VERSION 5.7 ;
  NOWIREEXTENSIONATPIN ON ;
  DIVIDERCHAR "/" ;
  BUSBITCHARS "[]" ;
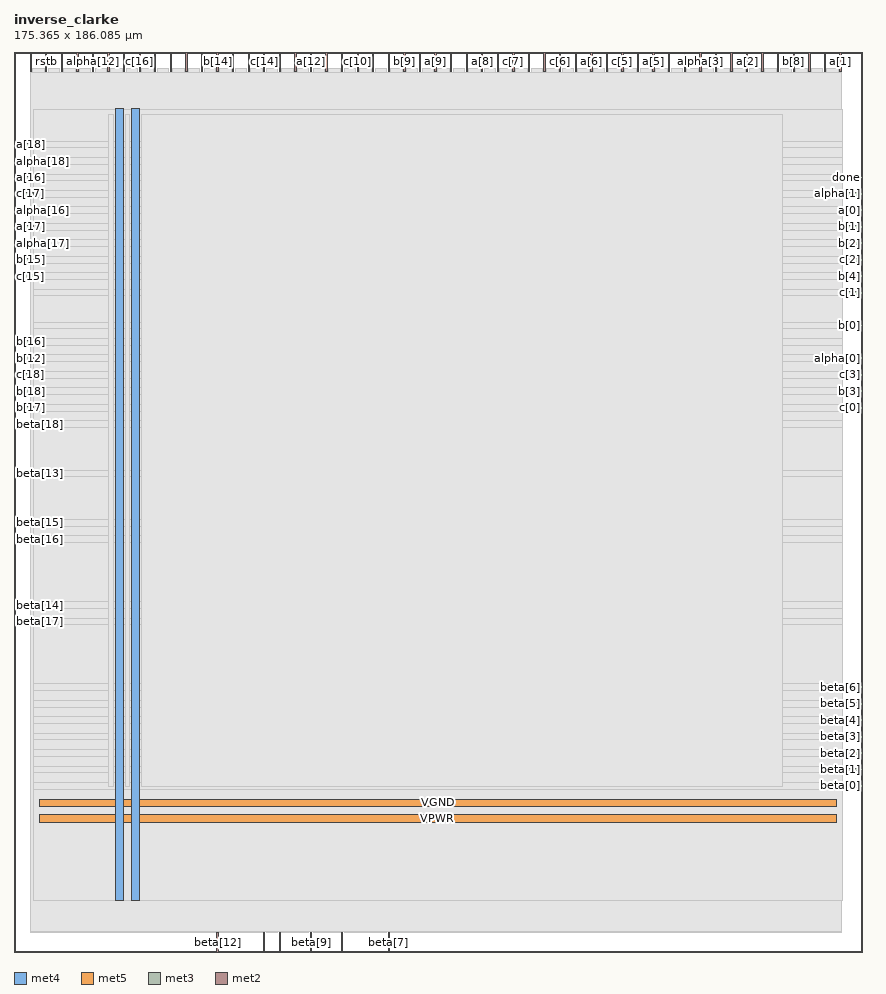
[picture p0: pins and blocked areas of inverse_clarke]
MACRO inverse_clarke
  CLASS BLOCK ;
  FOREIGN inverse_clarke ;
  ORIGIN 0.000 0.000 ;
  SIZE 175.365 BY 186.085 ;
  PIN VGND
    DIRECTION INOUT ;
    USE GROUND ;
    PORT
      LAYER met4 ;
        RECT 24.340 10.640 25.940 174.320 ;
    END
    PORT
      LAYER met5 ;
        RECT 5.280 30.030 169.980 31.630 ;
    END
  END VGND
  PIN VPWR
    DIRECTION INOUT ;
    USE POWER ;
    PORT
      LAYER met4 ;
        RECT 21.040 10.640 22.640 174.320 ;
    END
    PORT
      LAYER met5 ;
        RECT 5.280 26.730 169.980 28.330 ;
    END
  END VPWR
  PIN a[0]
    DIRECTION OUTPUT ;
    USE SIGNAL ;
    ANTENNADIFFAREA 0.795200 ;
    PORT
      LAYER met3 ;
        RECT 171.365 153.040 175.365 153.640 ;
    END
  END a[0]
  PIN a[10]
    DIRECTION OUTPUT ;
    USE SIGNAL ;
    ANTENNADIFFAREA 0.795200 ;
    PORT
      LAYER met2 ;
        RECT 12.970 182.085 13.250 186.085 ;
    END
  END a[10]
  PIN a[11]
    DIRECTION OUTPUT ;
    USE SIGNAL ;
    ANTENNADIFFAREA 0.445500 ;
    PORT
      LAYER met2 ;
        RECT 45.170 182.085 45.450 186.085 ;
    END
  END a[11]
  PIN a[12]
    DIRECTION OUTPUT ;
    USE SIGNAL ;
    ANTENNADIFFAREA 0.795200 ;
    PORT
      LAYER met2 ;
        RECT 61.270 182.085 61.550 186.085 ;
    END
  END a[12]
  PIN a[13]
    DIRECTION OUTPUT ;
    USE SIGNAL ;
    ANTENNADIFFAREA 0.795200 ;
    PORT
      LAYER met2 ;
        RECT 19.410 182.085 19.690 186.085 ;
    END
  END a[13]
  PIN a[14]
    DIRECTION OUTPUT ;
    USE SIGNAL ;
    ANTENNADIFFAREA 0.795200 ;
    PORT
      LAYER met2 ;
        RECT 32.290 182.085 32.570 186.085 ;
    END
  END a[14]
  PIN a[15]
    DIRECTION OUTPUT ;
    USE SIGNAL ;
    ANTENNADIFFAREA 0.795200 ;
    PORT
      LAYER met2 ;
        RECT 29.070 182.085 29.350 186.085 ;
    END
  END a[15]
  PIN a[16]
    DIRECTION OUTPUT ;
    USE SIGNAL ;
    ANTENNADIFFAREA 0.795200 ;
    PORT
      LAYER met3 ;
        RECT 0.000 159.840 4.000 160.440 ;
    END
  END a[16]
  PIN a[17]
    DIRECTION OUTPUT ;
    USE SIGNAL ;
    ANTENNADIFFAREA 0.795200 ;
    PORT
      LAYER met3 ;
        RECT 0.000 149.640 4.000 150.240 ;
    END
  END a[17]
  PIN a[18]
    DIRECTION OUTPUT ;
    USE SIGNAL ;
    ANTENNADIFFAREA 0.795200 ;
    PORT
      LAYER met3 ;
        RECT 0.000 166.640 4.000 167.240 ;
    END
  END a[18]
  PIN a[1]
    DIRECTION OUTPUT ;
    USE SIGNAL ;
    ANTENNADIFFAREA 0.795200 ;
    PORT
      LAYER met2 ;
        RECT 170.750 182.085 171.030 186.085 ;
    END
  END a[1]
  PIN a[2]
    DIRECTION OUTPUT ;
    USE SIGNAL ;
    ANTENNADIFFAREA 0.795200 ;
    PORT
      LAYER met2 ;
        RECT 151.430 182.085 151.710 186.085 ;
    END
  END a[2]
  PIN a[3]
    DIRECTION OUTPUT ;
    USE SIGNAL ;
    ANTENNADIFFAREA 0.795200 ;
    PORT
      LAYER met2 ;
        RECT 148.210 182.085 148.490 186.085 ;
    END
  END a[3]
  PIN a[4]
    DIRECTION OUTPUT ;
    USE SIGNAL ;
    ANTENNADIFFAREA 0.795200 ;
    PORT
      LAYER met2 ;
        RECT 154.650 182.085 154.930 186.085 ;
    END
  END a[4]
  PIN a[5]
    DIRECTION OUTPUT ;
    USE SIGNAL ;
    ANTENNADIFFAREA 0.795200 ;
    PORT
      LAYER met2 ;
        RECT 132.110 182.085 132.390 186.085 ;
    END
  END a[5]
  PIN a[6]
    DIRECTION OUTPUT ;
    USE SIGNAL ;
    ANTENNADIFFAREA 0.795200 ;
    PORT
      LAYER met2 ;
        RECT 119.230 182.085 119.510 186.085 ;
    END
  END a[6]
  PIN a[7]
    DIRECTION OUTPUT ;
    USE SIGNAL ;
    ANTENNADIFFAREA 0.795200 ;
    PORT
      LAYER met2 ;
        RECT 167.530 182.085 167.810 186.085 ;
    END
  END a[7]
  PIN a[8]
    DIRECTION OUTPUT ;
    USE SIGNAL ;
    ANTENNADIFFAREA 0.795200 ;
    PORT
      LAYER met2 ;
        RECT 96.690 182.085 96.970 186.085 ;
    END
  END a[8]
  PIN a[9]
    DIRECTION OUTPUT ;
    USE SIGNAL ;
    ANTENNADIFFAREA 0.795200 ;
    PORT
      LAYER met2 ;
        RECT 87.030 182.085 87.310 186.085 ;
    END
  END a[9]
  PIN alpha[0]
    DIRECTION INPUT ;
    USE SIGNAL ;
    ANTENNAGATEAREA 0.196500 ;
    PORT
      LAYER met3 ;
        RECT 171.365 122.440 175.365 123.040 ;
    END
  END alpha[0]
  PIN alpha[10]
    DIRECTION INPUT ;
    USE SIGNAL ;
    ANTENNAGATEAREA 0.213000 ;
    PORT
      LAYER met2 ;
        RECT 54.830 182.085 55.110 186.085 ;
    END
  END alpha[10]
  PIN alpha[11]
    DIRECTION INPUT ;
    USE SIGNAL ;
    ANTENNAGATEAREA 0.196500 ;
    PORT
      LAYER met2 ;
        RECT 74.150 182.085 74.430 186.085 ;
    END
  END alpha[11]
  PIN alpha[12]
    DIRECTION INPUT ;
    USE SIGNAL ;
    ANTENNAGATEAREA 0.196500 ;
    PORT
      LAYER met2 ;
        RECT 16.190 182.085 16.470 186.085 ;
    END
  END alpha[12]
  PIN alpha[13]
    DIRECTION INPUT ;
    USE SIGNAL ;
    ANTENNAGATEAREA 0.159000 ;
    PORT
      LAYER met2 ;
        RECT 35.510 182.085 35.790 186.085 ;
    END
  END alpha[13]
  PIN alpha[14]
    DIRECTION INPUT ;
    USE SIGNAL ;
    ANTENNAGATEAREA 0.196500 ;
    PORT
      LAYER met2 ;
        RECT 38.730 182.085 39.010 186.085 ;
    END
  END alpha[14]
  PIN alpha[15]
    DIRECTION INPUT ;
    USE SIGNAL ;
    ANTENNAGATEAREA 0.196500 ;
    PORT
      LAYER met2 ;
        RECT 22.630 182.085 22.910 186.085 ;
    END
  END alpha[15]
  PIN alpha[16]
    DIRECTION INPUT ;
    USE SIGNAL ;
    ANTENNAGATEAREA 0.196500 ;
    PORT
      LAYER met3 ;
        RECT 0.000 153.040 4.000 153.640 ;
    END
  END alpha[16]
  PIN alpha[17]
    DIRECTION INPUT ;
    USE SIGNAL ;
    ANTENNAGATEAREA 0.196500 ;
    PORT
      LAYER met3 ;
        RECT 0.000 146.240 4.000 146.840 ;
    END
  END alpha[17]
  PIN alpha[18]
    DIRECTION INPUT ;
    USE SIGNAL ;
    ANTENNAGATEAREA 0.196500 ;
    PORT
      LAYER met3 ;
        RECT 0.000 163.240 4.000 163.840 ;
    END
  END alpha[18]
  PIN alpha[1]
    DIRECTION INPUT ;
    USE SIGNAL ;
    ANTENNAGATEAREA 0.196500 ;
    PORT
      LAYER met3 ;
        RECT 171.365 156.440 175.365 157.040 ;
    END
  END alpha[1]
  PIN alpha[2]
    DIRECTION INPUT ;
    USE SIGNAL ;
    ANTENNAGATEAREA 0.213000 ;
    PORT
      LAYER met2 ;
        RECT 144.990 182.085 145.270 186.085 ;
    END
  END alpha[2]
  PIN alpha[3]
    DIRECTION INPUT ;
    USE SIGNAL ;
    ANTENNAGATEAREA 0.196500 ;
    PORT
      LAYER met2 ;
        RECT 141.770 182.085 142.050 186.085 ;
    END
  END alpha[3]
  PIN alpha[4]
    DIRECTION INPUT ;
    USE SIGNAL ;
    ANTENNAGATEAREA 0.213000 ;
    PORT
      LAYER met2 ;
        RECT 138.550 182.085 138.830 186.085 ;
    END
  END alpha[4]
  PIN alpha[5]
    DIRECTION INPUT ;
    USE SIGNAL ;
    ANTENNAGATEAREA 0.196500 ;
    PORT
      LAYER met2 ;
        RECT 128.890 182.085 129.170 186.085 ;
    END
  END alpha[5]
  PIN alpha[6]
    DIRECTION INPUT ;
    USE SIGNAL ;
    ANTENNAGATEAREA 0.196500 ;
    PORT
      LAYER met2 ;
        RECT 157.870 182.085 158.150 186.085 ;
    END
  END alpha[6]
  PIN alpha[7]
    DIRECTION INPUT ;
    USE SIGNAL ;
    ANTENNAGATEAREA 0.126000 ;
    PORT
      LAYER met2 ;
        RECT 106.350 182.085 106.630 186.085 ;
    END
  END alpha[7]
  PIN alpha[8]
    DIRECTION INPUT ;
    USE SIGNAL ;
    ANTENNAGATEAREA 0.196500 ;
    PORT
      LAYER met2 ;
        RECT 99.910 182.085 100.190 186.085 ;
    END
  END alpha[8]
  PIN alpha[9]
    DIRECTION INPUT ;
    USE SIGNAL ;
    ANTENNAGATEAREA 0.196500 ;
    PORT
      LAYER met2 ;
        RECT 83.810 182.085 84.090 186.085 ;
    END
  END alpha[9]
  PIN b[0]
    DIRECTION OUTPUT ;
    USE SIGNAL ;
    ANTENNADIFFAREA 0.795200 ;
    PORT
      LAYER met3 ;
        RECT 171.365 129.240 175.365 129.840 ;
    END
  END b[0]
  PIN b[10]
    DIRECTION OUTPUT ;
    USE SIGNAL ;
    ANTENNADIFFAREA 0.795200 ;
    PORT
      LAYER met2 ;
        RECT 77.370 182.085 77.650 186.085 ;
    END
  END b[10]
  PIN b[11]
    DIRECTION OUTPUT ;
    USE SIGNAL ;
    ANTENNADIFFAREA 0.795200 ;
    PORT
      LAYER met2 ;
        RECT 64.490 182.085 64.770 186.085 ;
    END
  END b[11]
  PIN b[12]
    DIRECTION OUTPUT ;
    USE SIGNAL ;
    ANTENNADIFFAREA 0.795200 ;
    PORT
      LAYER met3 ;
        RECT 0.000 122.440 4.000 123.040 ;
    END
  END b[12]
  PIN b[13]
    DIRECTION OUTPUT ;
    USE SIGNAL ;
    ANTENNADIFFAREA 0.795200 ;
    PORT
      LAYER met2 ;
        RECT 48.390 182.085 48.670 186.085 ;
    END
  END b[13]
  PIN b[14]
    DIRECTION OUTPUT ;
    USE SIGNAL ;
    ANTENNADIFFAREA 0.795200 ;
    PORT
      LAYER met2 ;
        RECT 41.950 182.085 42.230 186.085 ;
    END
  END b[14]
  PIN b[15]
    DIRECTION OUTPUT ;
    USE SIGNAL ;
    ANTENNADIFFAREA 0.795200 ;
    PORT
      LAYER met3 ;
        RECT 0.000 142.840 4.000 143.440 ;
    END
  END b[15]
  PIN b[16]
    DIRECTION OUTPUT ;
    USE SIGNAL ;
    ANTENNADIFFAREA 0.795200 ;
    PORT
      LAYER met3 ;
        RECT 0.000 125.840 4.000 126.440 ;
    END
  END b[16]
  PIN b[17]
    DIRECTION OUTPUT ;
    USE SIGNAL ;
    ANTENNADIFFAREA 0.795200 ;
    PORT
      LAYER met3 ;
        RECT 0.000 112.240 4.000 112.840 ;
    END
  END b[17]
  PIN b[18]
    DIRECTION OUTPUT ;
    USE SIGNAL ;
    ANTENNADIFFAREA 0.795200 ;
    PORT
      LAYER met3 ;
        RECT 0.000 115.640 4.000 116.240 ;
    END
  END b[18]
  PIN b[1]
    DIRECTION OUTPUT ;
    USE SIGNAL ;
    ANTENNADIFFAREA 0.445500 ;
    PORT
      LAYER met3 ;
        RECT 171.365 149.640 175.365 150.240 ;
    END
  END b[1]
  PIN b[2]
    DIRECTION OUTPUT ;
    USE SIGNAL ;
    ANTENNADIFFAREA 0.445500 ;
    PORT
      LAYER met3 ;
        RECT 171.365 146.240 175.365 146.840 ;
    END
  END b[2]
  PIN b[3]
    DIRECTION OUTPUT ;
    USE SIGNAL ;
    ANTENNADIFFAREA 0.795200 ;
    PORT
      LAYER met3 ;
        RECT 171.365 115.640 175.365 116.240 ;
    END
  END b[3]
  PIN b[4]
    DIRECTION OUTPUT ;
    USE SIGNAL ;
    ANTENNADIFFAREA 0.445500 ;
    PORT
      LAYER met3 ;
        RECT 171.365 139.440 175.365 140.040 ;
    END
  END b[4]
  PIN b[5]
    DIRECTION OUTPUT ;
    USE SIGNAL ;
    ANTENNADIFFAREA 0.795200 ;
    PORT
      LAYER met2 ;
        RECT 122.450 182.085 122.730 186.085 ;
    END
  END b[5]
  PIN b[6]
    DIRECTION OUTPUT ;
    USE SIGNAL ;
    ANTENNADIFFAREA 0.795200 ;
    PORT
      LAYER met2 ;
        RECT 116.010 182.085 116.290 186.085 ;
    END
  END b[6]
  PIN b[7]
    DIRECTION OUTPUT ;
    USE SIGNAL ;
    ANTENNADIFFAREA 0.795200 ;
    PORT
      LAYER met2 ;
        RECT 109.570 182.085 109.850 186.085 ;
    END
  END b[7]
  PIN b[8]
    DIRECTION OUTPUT ;
    USE SIGNAL ;
    ANTENNADIFFAREA 0.795200 ;
    PORT
      LAYER met2 ;
        RECT 161.090 182.085 161.370 186.085 ;
    END
  END b[8]
  PIN b[9]
    DIRECTION OUTPUT ;
    USE SIGNAL ;
    ANTENNADIFFAREA 0.795200 ;
    PORT
      LAYER met2 ;
        RECT 80.590 182.085 80.870 186.085 ;
    END
  END b[9]
  PIN beta[0]
    DIRECTION INPUT ;
    USE SIGNAL ;
    ANTENNAGATEAREA 0.213000 ;
    PORT
      LAYER met3 ;
        RECT 171.365 34.040 175.365 34.640 ;
    END
  END beta[0]
  PIN beta[10]
    DIRECTION INPUT ;
    USE SIGNAL ;
    ANTENNAGATEAREA 0.196500 ;
    PORT
      LAYER met2 ;
        RECT 51.610 0.000 51.890 4.000 ;
    END
  END beta[10]
  PIN beta[11]
    DIRECTION INPUT ;
    USE SIGNAL ;
    ANTENNAGATEAREA 0.196500 ;
    PORT
      LAYER met2 ;
        RECT 54.830 0.000 55.110 4.000 ;
    END
  END beta[11]
  PIN beta[12]
    DIRECTION INPUT ;
    USE SIGNAL ;
    ANTENNAGATEAREA 0.196500 ;
    PORT
      LAYER met2 ;
        RECT 41.950 0.000 42.230 4.000 ;
    END
  END beta[12]
  PIN beta[13]
    DIRECTION INPUT ;
    USE SIGNAL ;
    ANTENNAGATEAREA 0.196500 ;
    PORT
      LAYER met3 ;
        RECT 0.000 98.640 4.000 99.240 ;
    END
  END beta[13]
  PIN beta[14]
    DIRECTION INPUT ;
    USE SIGNAL ;
    ANTENNAGATEAREA 0.196500 ;
    PORT
      LAYER met3 ;
        RECT 0.000 71.440 4.000 72.040 ;
    END
  END beta[14]
  PIN beta[15]
    DIRECTION INPUT ;
    USE SIGNAL ;
    ANTENNAGATEAREA 0.196500 ;
    PORT
      LAYER met3 ;
        RECT 0.000 88.440 4.000 89.040 ;
    END
  END beta[15]
  PIN beta[16]
    DIRECTION INPUT ;
    USE SIGNAL ;
    ANTENNAGATEAREA 0.196500 ;
    PORT
      LAYER met3 ;
        RECT 0.000 85.040 4.000 85.640 ;
    END
  END beta[16]
  PIN beta[17]
    DIRECTION INPUT ;
    USE SIGNAL ;
    ANTENNAGATEAREA 0.196500 ;
    PORT
      LAYER met3 ;
        RECT 0.000 68.040 4.000 68.640 ;
    END
  END beta[17]
  PIN beta[18]
    DIRECTION INPUT ;
    USE SIGNAL ;
    ANTENNAGATEAREA 0.196500 ;
    PORT
      LAYER met3 ;
        RECT 0.000 108.840 4.000 109.440 ;
    END
  END beta[18]
  PIN beta[1]
    DIRECTION INPUT ;
    USE SIGNAL ;
    ANTENNAGATEAREA 0.159000 ;
    PORT
      LAYER met3 ;
        RECT 171.365 37.440 175.365 38.040 ;
    END
  END beta[1]
  PIN beta[2]
    DIRECTION INPUT ;
    USE SIGNAL ;
    ANTENNAGATEAREA 0.196500 ;
    PORT
      LAYER met3 ;
        RECT 171.365 40.840 175.365 41.440 ;
    END
  END beta[2]
  PIN beta[3]
    DIRECTION INPUT ;
    USE SIGNAL ;
    ANTENNAGATEAREA 0.196500 ;
    PORT
      LAYER met3 ;
        RECT 171.365 44.240 175.365 44.840 ;
    END
  END beta[3]
  PIN beta[4]
    DIRECTION INPUT ;
    USE SIGNAL ;
    ANTENNAGATEAREA 0.495000 ;
    PORT
      LAYER met3 ;
        RECT 171.365 47.640 175.365 48.240 ;
    END
  END beta[4]
  PIN beta[5]
    DIRECTION INPUT ;
    USE SIGNAL ;
    ANTENNAGATEAREA 0.196500 ;
    PORT
      LAYER met3 ;
        RECT 171.365 51.040 175.365 51.640 ;
    END
  END beta[5]
  PIN beta[6]
    DIRECTION INPUT ;
    USE SIGNAL ;
    ANTENNAGATEAREA 0.196500 ;
    PORT
      LAYER met3 ;
        RECT 171.365 54.440 175.365 55.040 ;
    END
  END beta[6]
  PIN beta[7]
    DIRECTION INPUT ;
    USE SIGNAL ;
    ANTENNAGATEAREA 0.213000 ;
    PORT
      LAYER met2 ;
        RECT 77.370 0.000 77.650 4.000 ;
    END
  END beta[7]
  PIN beta[8]
    DIRECTION INPUT ;
    USE SIGNAL ;
    ANTENNAGATEAREA 0.196500 ;
    PORT
      LAYER met2 ;
        RECT 67.710 0.000 67.990 4.000 ;
    END
  END beta[8]
  PIN beta[9]
    DIRECTION INPUT ;
    USE SIGNAL ;
    ANTENNAGATEAREA 0.196500 ;
    PORT
      LAYER met2 ;
        RECT 61.270 0.000 61.550 4.000 ;
    END
  END beta[9]
  PIN c[0]
    DIRECTION OUTPUT ;
    USE SIGNAL ;
    ANTENNADIFFAREA 0.445500 ;
    PORT
      LAYER met3 ;
        RECT 171.365 112.240 175.365 112.840 ;
    END
  END c[0]
  PIN c[10]
    DIRECTION OUTPUT ;
    USE SIGNAL ;
    ANTENNADIFFAREA 0.795200 ;
    PORT
      LAYER met2 ;
        RECT 70.930 182.085 71.210 186.085 ;
    END
  END c[10]
  PIN c[11]
    DIRECTION OUTPUT ;
    USE SIGNAL ;
    ANTENNADIFFAREA 0.795200 ;
    PORT
      LAYER met2 ;
        RECT 67.710 182.085 67.990 186.085 ;
    END
  END c[11]
  PIN c[12]
    DIRECTION OUTPUT ;
    USE SIGNAL ;
    ANTENNADIFFAREA 0.795200 ;
    PORT
      LAYER met2 ;
        RECT 9.750 182.085 10.030 186.085 ;
    END
  END c[12]
  PIN c[13]
    DIRECTION OUTPUT ;
    USE SIGNAL ;
    ANTENNADIFFAREA 0.795200 ;
    PORT
      LAYER met2 ;
        RECT 58.050 182.085 58.330 186.085 ;
    END
  END c[13]
  PIN c[14]
    DIRECTION OUTPUT ;
    USE SIGNAL ;
    ANTENNADIFFAREA 0.795200 ;
    PORT
      LAYER met2 ;
        RECT 51.610 182.085 51.890 186.085 ;
    END
  END c[14]
  PIN c[15]
    DIRECTION OUTPUT ;
    USE SIGNAL ;
    ANTENNADIFFAREA 0.795200 ;
    PORT
      LAYER met3 ;
        RECT 0.000 139.440 4.000 140.040 ;
    END
  END c[15]
  PIN c[16]
    DIRECTION OUTPUT ;
    USE SIGNAL ;
    ANTENNADIFFAREA 0.795200 ;
    PORT
      LAYER met2 ;
        RECT 25.850 182.085 26.130 186.085 ;
    END
  END c[16]
  PIN c[17]
    DIRECTION OUTPUT ;
    USE SIGNAL ;
    ANTENNADIFFAREA 0.795200 ;
    PORT
      LAYER met3 ;
        RECT 0.000 156.440 4.000 157.040 ;
    END
  END c[17]
  PIN c[18]
    DIRECTION OUTPUT ;
    USE SIGNAL ;
    ANTENNADIFFAREA 0.795200 ;
    PORT
      LAYER met3 ;
        RECT 0.000 119.040 4.000 119.640 ;
    END
  END c[18]
  PIN c[1]
    DIRECTION OUTPUT ;
    USE SIGNAL ;
    ANTENNADIFFAREA 0.795200 ;
    PORT
      LAYER met3 ;
        RECT 171.365 136.040 175.365 136.640 ;
    END
  END c[1]
  PIN c[2]
    DIRECTION OUTPUT ;
    USE SIGNAL ;
    ANTENNADIFFAREA 0.795200 ;
    PORT
      LAYER met3 ;
        RECT 171.365 142.840 175.365 143.440 ;
    END
  END c[2]
  PIN c[3]
    DIRECTION OUTPUT ;
    USE SIGNAL ;
    ANTENNADIFFAREA 0.445500 ;
    PORT
      LAYER met3 ;
        RECT 171.365 119.040 175.365 119.640 ;
    END
  END c[3]
  PIN c[4]
    DIRECTION OUTPUT ;
    USE SIGNAL ;
    ANTENNADIFFAREA 0.795200 ;
    PORT
      LAYER met2 ;
        RECT 135.330 182.085 135.610 186.085 ;
    END
  END c[4]
  PIN c[5]
    DIRECTION OUTPUT ;
    USE SIGNAL ;
    ANTENNADIFFAREA 0.795200 ;
    PORT
      LAYER met2 ;
        RECT 125.670 182.085 125.950 186.085 ;
    END
  END c[5]
  PIN c[6]
    DIRECTION OUTPUT ;
    USE SIGNAL ;
    ANTENNADIFFAREA 0.795200 ;
    PORT
      LAYER met2 ;
        RECT 112.790 182.085 113.070 186.085 ;
    END
  END c[6]
  PIN c[7]
    DIRECTION OUTPUT ;
    USE SIGNAL ;
    ANTENNADIFFAREA 0.795200 ;
    PORT
      LAYER met2 ;
        RECT 103.130 182.085 103.410 186.085 ;
    END
  END c[7]
  PIN c[8]
    DIRECTION OUTPUT ;
    USE SIGNAL ;
    ANTENNADIFFAREA 0.445500 ;
    PORT
      LAYER met2 ;
        RECT 93.470 182.085 93.750 186.085 ;
    END
  END c[8]
  PIN c[9]
    DIRECTION OUTPUT ;
    USE SIGNAL ;
    ANTENNADIFFAREA 0.795200 ;
    PORT
      LAYER met2 ;
        RECT 90.250 182.085 90.530 186.085 ;
    END
  END c[9]
  PIN clk
    DIRECTION INPUT ;
    USE SIGNAL ;
    ANTENNAGATEAREA 0.852000 ;
    PORT
      LAYER met2 ;
        RECT 3.310 182.085 3.590 186.085 ;
    END
  END clk
  PIN done
    DIRECTION OUTPUT ;
    USE SIGNAL ;
    ANTENNADIFFAREA 0.795200 ;
    PORT
      LAYER met3 ;
        RECT 171.365 159.840 175.365 160.440 ;
    END
  END done
  PIN rstb
    DIRECTION INPUT ;
    USE SIGNAL ;
    ANTENNAGATEAREA 0.213000 ;
    PORT
      LAYER met2 ;
        RECT 6.530 182.085 6.810 186.085 ;
    END
  END rstb
  PIN start
    DIRECTION INPUT ;
    USE SIGNAL ;
    ANTENNAGATEAREA 0.213000 ;
    PORT
      LAYER met2 ;
        RECT 164.310 182.085 164.590 186.085 ;
    END
  END start
  OBS
      LAYER li1 ;
        RECT 5.520 10.795 169.740 174.165 ;
      LAYER met1 ;
        RECT 4.670 10.640 171.050 175.060 ;
      LAYER met2 ;
        RECT 3.870 181.805 6.250 182.650 ;
        RECT 7.090 181.805 9.470 182.650 ;
        RECT 10.310 181.805 12.690 182.650 ;
        RECT 13.530 181.805 15.910 182.650 ;
        RECT 16.750 181.805 19.130 182.650 ;
        RECT 19.970 181.805 22.350 182.650 ;
        RECT 23.190 181.805 25.570 182.650 ;
        RECT 26.410 181.805 28.790 182.650 ;
        RECT 29.630 181.805 32.010 182.650 ;
        RECT 32.850 181.805 35.230 182.650 ;
        RECT 36.070 181.805 38.450 182.650 ;
        RECT 39.290 181.805 41.670 182.650 ;
        RECT 42.510 181.805 44.890 182.650 ;
        RECT 45.730 181.805 48.110 182.650 ;
        RECT 48.950 181.805 51.330 182.650 ;
        RECT 52.170 181.805 54.550 182.650 ;
        RECT 55.390 181.805 57.770 182.650 ;
        RECT 58.610 181.805 60.990 182.650 ;
        RECT 61.830 181.805 64.210 182.650 ;
        RECT 65.050 181.805 67.430 182.650 ;
        RECT 68.270 181.805 70.650 182.650 ;
        RECT 71.490 181.805 73.870 182.650 ;
        RECT 74.710 181.805 77.090 182.650 ;
        RECT 77.930 181.805 80.310 182.650 ;
        RECT 81.150 181.805 83.530 182.650 ;
        RECT 84.370 181.805 86.750 182.650 ;
        RECT 87.590 181.805 89.970 182.650 ;
        RECT 90.810 181.805 93.190 182.650 ;
        RECT 94.030 181.805 96.410 182.650 ;
        RECT 97.250 181.805 99.630 182.650 ;
        RECT 100.470 181.805 102.850 182.650 ;
        RECT 103.690 181.805 106.070 182.650 ;
        RECT 106.910 181.805 109.290 182.650 ;
        RECT 110.130 181.805 112.510 182.650 ;
        RECT 113.350 181.805 115.730 182.650 ;
        RECT 116.570 181.805 118.950 182.650 ;
        RECT 119.790 181.805 122.170 182.650 ;
        RECT 123.010 181.805 125.390 182.650 ;
        RECT 126.230 181.805 128.610 182.650 ;
        RECT 129.450 181.805 131.830 182.650 ;
        RECT 132.670 181.805 135.050 182.650 ;
        RECT 135.890 181.805 138.270 182.650 ;
        RECT 139.110 181.805 141.490 182.650 ;
        RECT 142.330 181.805 144.710 182.650 ;
        RECT 145.550 181.805 147.930 182.650 ;
        RECT 148.770 181.805 151.150 182.650 ;
        RECT 151.990 181.805 154.370 182.650 ;
        RECT 155.210 181.805 157.590 182.650 ;
        RECT 158.430 181.805 160.810 182.650 ;
        RECT 161.650 181.805 164.030 182.650 ;
        RECT 164.870 181.805 167.250 182.650 ;
        RECT 168.090 181.805 170.470 182.650 ;
        RECT 3.380 4.280 171.020 181.805 ;
        RECT 3.380 4.000 41.670 4.280 ;
        RECT 42.510 4.000 51.330 4.280 ;
        RECT 52.170 4.000 54.550 4.280 ;
        RECT 55.390 4.000 60.990 4.280 ;
        RECT 61.830 4.000 67.430 4.280 ;
        RECT 68.270 4.000 77.090 4.280 ;
        RECT 77.930 4.000 171.020 4.280 ;
      LAYER met3 ;
        RECT 3.990 167.640 171.365 174.245 ;
        RECT 4.400 166.240 171.365 167.640 ;
        RECT 3.990 164.240 171.365 166.240 ;
        RECT 4.400 162.840 171.365 164.240 ;
        RECT 3.990 160.840 171.365 162.840 ;
        RECT 4.400 159.440 170.965 160.840 ;
        RECT 3.990 157.440 171.365 159.440 ;
        RECT 4.400 156.040 170.965 157.440 ;
        RECT 3.990 154.040 171.365 156.040 ;
        RECT 4.400 152.640 170.965 154.040 ;
        RECT 3.990 150.640 171.365 152.640 ;
        RECT 4.400 149.240 170.965 150.640 ;
        RECT 3.990 147.240 171.365 149.240 ;
        RECT 4.400 145.840 170.965 147.240 ;
        RECT 3.990 143.840 171.365 145.840 ;
        RECT 4.400 142.440 170.965 143.840 ;
        RECT 3.990 140.440 171.365 142.440 ;
        RECT 4.400 139.040 170.965 140.440 ;
        RECT 3.990 137.040 171.365 139.040 ;
        RECT 3.990 135.640 170.965 137.040 ;
        RECT 3.990 130.240 171.365 135.640 ;
        RECT 3.990 128.840 170.965 130.240 ;
        RECT 3.990 126.840 171.365 128.840 ;
        RECT 4.400 125.440 171.365 126.840 ;
        RECT 3.990 123.440 171.365 125.440 ;
        RECT 4.400 122.040 170.965 123.440 ;
        RECT 3.990 120.040 171.365 122.040 ;
        RECT 4.400 118.640 170.965 120.040 ;
        RECT 3.990 116.640 171.365 118.640 ;
        RECT 4.400 115.240 170.965 116.640 ;
        RECT 3.990 113.240 171.365 115.240 ;
        RECT 4.400 111.840 170.965 113.240 ;
        RECT 3.990 109.840 171.365 111.840 ;
        RECT 4.400 108.440 171.365 109.840 ;
        RECT 3.990 99.640 171.365 108.440 ;
        RECT 4.400 98.240 171.365 99.640 ;
        RECT 3.990 89.440 171.365 98.240 ;
        RECT 4.400 88.040 171.365 89.440 ;
        RECT 3.990 86.040 171.365 88.040 ;
        RECT 4.400 84.640 171.365 86.040 ;
        RECT 3.990 72.440 171.365 84.640 ;
        RECT 4.400 71.040 171.365 72.440 ;
        RECT 3.990 69.040 171.365 71.040 ;
        RECT 4.400 67.640 171.365 69.040 ;
        RECT 3.990 55.440 171.365 67.640 ;
        RECT 3.990 54.040 170.965 55.440 ;
        RECT 3.990 52.040 171.365 54.040 ;
        RECT 3.990 50.640 170.965 52.040 ;
        RECT 3.990 48.640 171.365 50.640 ;
        RECT 3.990 47.240 170.965 48.640 ;
        RECT 3.990 45.240 171.365 47.240 ;
        RECT 3.990 43.840 170.965 45.240 ;
        RECT 3.990 41.840 171.365 43.840 ;
        RECT 3.990 40.440 170.965 41.840 ;
        RECT 3.990 38.440 171.365 40.440 ;
        RECT 3.990 37.040 170.965 38.440 ;
        RECT 3.990 35.040 171.365 37.040 ;
        RECT 3.990 33.640 170.965 35.040 ;
        RECT 3.990 10.715 171.365 33.640 ;
      LAYER met4 ;
        RECT 19.615 34.175 20.640 173.225 ;
        RECT 23.040 34.175 23.940 173.225 ;
        RECT 26.340 34.175 158.865 173.225 ;
  END
END inverse_clarke
END LIBRARY

